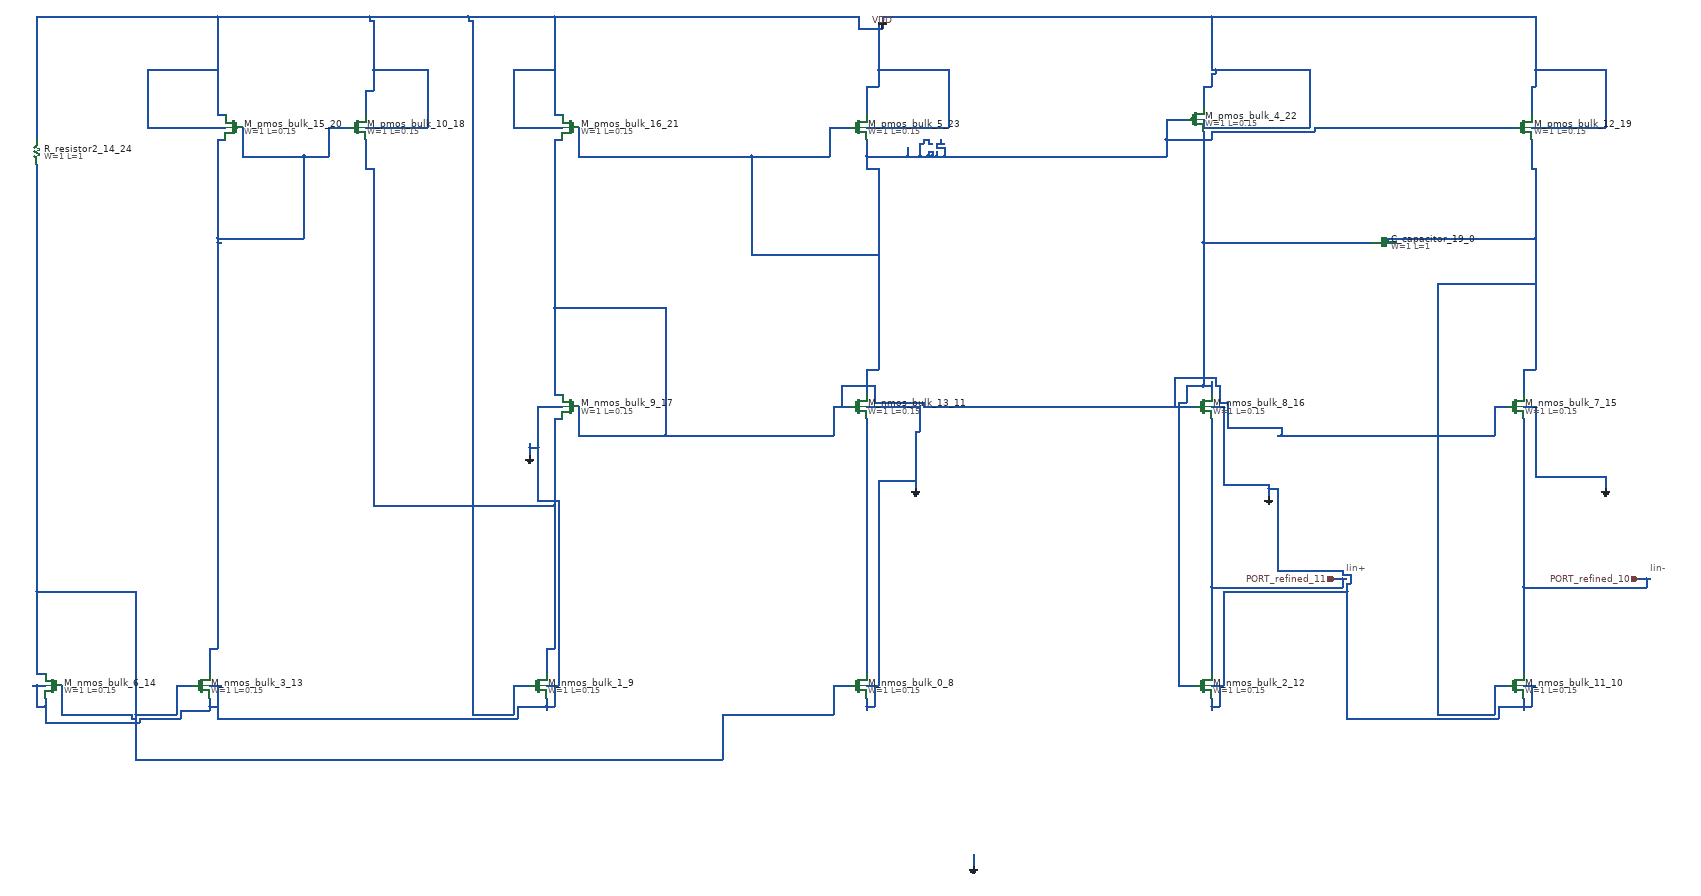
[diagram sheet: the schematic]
v {xschem version=3.4.8 file_version=1.2}
G {}
K {}
V {}
S {}
E {}
C {sky130_fd_pr/cap_mim_m3_1.sym} 3580 700 1 0 {name="C_capacitor_19_0" model=cap_mim_m3_1 W=1 L=1 MF=1 spiceprefix=X}
C {devices/gnd.sym} 1500 1220 0 0 {name="l_gnd_17_1" lab="GND"}
C {devices/gnd.sym} 2440 1300 0 0 {name="l_gnd_18_2" lab="GND"}
C {devices/gnd.sym} 3300 1320 0 0 {name="l_gnd_20_3" lab="GND"}
C {devices/gnd.sym} 4120 1300 0 0 {name="l_gnd_21_4" lab="GND"}
C {devices/gnd.sym} 2580 2220 0 0 {name="l_gnd_22_5" lab="GND"}
C {devices/ipin.sym} 4200 1520 0 0 {name="p_gnd_23_6" lab="PORT_refined_10"}
T {Iin-} 4230 1480 0 0 0.25 0.25 {}
C {devices/ipin.sym} 3460 1520 0 0 {name="p_gnd_24_7" lab="PORT_refined_11"}
T {Iin+} 3490 1480 0 0 0.25 0.25 {}
C {sky130_fd_pr/nfet_01v8.sym} 2300 1780 0 0 {name="M_nmos_bulk_0_8"
W=1
L=0.15
nf=1 
mult=1
ad="expr('int((@nf + 1)/2) * @W / @nf * 0.29')"
pd="expr('2*int((@nf + 1)/2) * (@W / @nf + 0.29)')"
as="expr('int((@nf + 2)/2) * @W / @nf * 0.29')"
ps="expr('2*int((@nf + 2)/2) * (@W / @nf + 0.29)')"
nrd="expr('0.29 / @W ')" nrs="expr('0.29 / @W ')"
sa=0 sb=0 sd=0
model=nfet_01v8
spiceprefix=X
}
C {sky130_fd_pr/nfet_01v8.sym} 1520 1780 0 0 {name="M_nmos_bulk_1_9"
W=1
L=0.15
nf=1 
mult=1
ad="expr('int((@nf + 1)/2) * @W / @nf * 0.29')"
pd="expr('2*int((@nf + 1)/2) * (@W / @nf + 0.29)')"
as="expr('int((@nf + 2)/2) * @W / @nf * 0.29')"
ps="expr('2*int((@nf + 2)/2) * (@W / @nf + 0.29)')"
nrd="expr('0.29 / @W ')" nrs="expr('0.29 / @W ')"
sa=0 sb=0 sd=0
model=nfet_01v8
spiceprefix=X
}
C {sky130_fd_pr/nfet_01v8.sym} 3900 1780 0 0 {name="M_nmos_bulk_11_10"
W=1
L=0.15
nf=1 
mult=1
ad="expr('int((@nf + 1)/2) * @W / @nf * 0.29')"
pd="expr('2*int((@nf + 1)/2) * (@W / @nf + 0.29)')"
as="expr('int((@nf + 2)/2) * @W / @nf * 0.29')"
ps="expr('2*int((@nf + 2)/2) * (@W / @nf + 0.29)')"
nrd="expr('0.29 / @W ')" nrs="expr('0.29 / @W ')"
sa=0 sb=0 sd=0
model=nfet_01v8
spiceprefix=X
}
C {sky130_fd_pr/nfet_01v8.sym} 2300 1100 0 0 {name="M_nmos_bulk_13_11"
W=1
L=0.15
nf=1 
mult=1
ad="expr('int((@nf + 1)/2) * @W / @nf * 0.29')"
pd="expr('2*int((@nf + 1)/2) * (@W / @nf + 0.29)')"
as="expr('int((@nf + 2)/2) * @W / @nf * 0.29')"
ps="expr('2*int((@nf + 2)/2) * (@W / @nf + 0.29)')"
nrd="expr('0.29 / @W ')" nrs="expr('0.29 / @W ')"
sa=0 sb=0 sd=0
model=nfet_01v8
spiceprefix=X
}
C {sky130_fd_pr/nfet_01v8.sym} 3140 1780 0 0 {name="M_nmos_bulk_2_12"
W=1
L=0.15
nf=1 
mult=1
ad="expr('int((@nf + 1)/2) * @W / @nf * 0.29')"
pd="expr('2*int((@nf + 1)/2) * (@W / @nf + 0.29)')"
as="expr('int((@nf + 2)/2) * @W / @nf * 0.29')"
ps="expr('2*int((@nf + 2)/2) * (@W / @nf + 0.29)')"
nrd="expr('0.29 / @W ')" nrs="expr('0.29 / @W ')"
sa=0 sb=0 sd=0
model=nfet_01v8
spiceprefix=X
}
C {sky130_fd_pr/nfet_01v8.sym} 700 1780 0 0 {name="M_nmos_bulk_3_13"
W=1
L=0.15
nf=1 
mult=1
ad="expr('int((@nf + 1)/2) * @W / @nf * 0.29')"
pd="expr('2*int((@nf + 1)/2) * (@W / @nf + 0.29)')"
as="expr('int((@nf + 2)/2) * @W / @nf * 0.29')"
ps="expr('2*int((@nf + 2)/2) * (@W / @nf + 0.29)')"
nrd="expr('0.29 / @W ')" nrs="expr('0.29 / @W ')"
sa=0 sb=0 sd=0
model=nfet_01v8
spiceprefix=X
}
C {sky130_fd_pr/nfet_01v8.sym} 340 1780 0 1 {name="M_nmos_bulk_6_14"
W=1
L=0.15
nf=1 
mult=1
ad="expr('int((@nf + 1)/2) * @W / @nf * 0.29')"
pd="expr('2*int((@nf + 1)/2) * (@W / @nf + 0.29)')"
as="expr('int((@nf + 2)/2) * @W / @nf * 0.29')"
ps="expr('2*int((@nf + 2)/2) * (@W / @nf + 0.29)')"
nrd="expr('0.29 / @W ')" nrs="expr('0.29 / @W ')"
sa=0 sb=0 sd=0
model=nfet_01v8
spiceprefix=X
}
C {sky130_fd_pr/nfet_01v8.sym} 3900 1100 0 0 {name="M_nmos_bulk_7_15"
W=1
L=0.15
nf=1 
mult=1
ad="expr('int((@nf + 1)/2) * @W / @nf * 0.29')"
pd="expr('2*int((@nf + 1)/2) * (@W / @nf + 0.29)')"
as="expr('int((@nf + 2)/2) * @W / @nf * 0.29')"
ps="expr('2*int((@nf + 2)/2) * (@W / @nf + 0.29)')"
nrd="expr('0.29 / @W ')" nrs="expr('0.29 / @W ')"
sa=0 sb=0 sd=0
model=nfet_01v8
spiceprefix=X
}
C {sky130_fd_pr/nfet_01v8.sym} 3140 1100 0 0 {name="M_nmos_bulk_8_16"
W=1
L=0.15
nf=1 
mult=1
ad="expr('int((@nf + 1)/2) * @W / @nf * 0.29')"
pd="expr('2*int((@nf + 1)/2) * (@W / @nf + 0.29)')"
as="expr('int((@nf + 2)/2) * @W / @nf * 0.29')"
ps="expr('2*int((@nf + 2)/2) * (@W / @nf + 0.29)')"
nrd="expr('0.29 / @W ')" nrs="expr('0.29 / @W ')"
sa=0 sb=0 sd=0
model=nfet_01v8
spiceprefix=X
}
C {sky130_fd_pr/nfet_01v8.sym} 1600 1100 0 1 {name="M_nmos_bulk_9_17"
W=1
L=0.15
nf=1 
mult=1
ad="expr('int((@nf + 1)/2) * @W / @nf * 0.29')"
pd="expr('2*int((@nf + 1)/2) * (@W / @nf + 0.29)')"
as="expr('int((@nf + 2)/2) * @W / @nf * 0.29')"
ps="expr('2*int((@nf + 2)/2) * (@W / @nf + 0.29)')"
nrd="expr('0.29 / @W ')" nrs="expr('0.29 / @W ')"
sa=0 sb=0 sd=0
model=nfet_01v8
spiceprefix=X
}
C {sky130_fd_pr/pfet_01v8.sym} 1080 420 0 0 {name="M_pmos_bulk_10_18"
W=1
L=0.15
nf=1
mult=1
ad="expr('int((@nf + 1)/2) * @W / @nf * 0.29')"
pd="expr('2*int((@nf + 1)/2) * (@W / @nf + 0.29)')"
as="expr('int((@nf + 2)/2) * @W / @nf * 0.29')"
ps="expr('2*int((@nf + 2)/2) * (@W / @nf + 0.29)')"
nrd="expr('0.29 / @W ')" nrs="expr('0.29 / @W ')"
sa=0 sb=0 sd=0
model=pfet_01v8
spiceprefix=X
}
C {sky130_fd_pr/pfet_01v8.sym} 3920 420 0 0 {name="M_pmos_bulk_12_19"
W=1
L=0.15
nf=1
mult=1
ad="expr('int((@nf + 1)/2) * @W / @nf * 0.29')"
pd="expr('2*int((@nf + 1)/2) * (@W / @nf + 0.29)')"
as="expr('int((@nf + 2)/2) * @W / @nf * 0.29')"
ps="expr('2*int((@nf + 2)/2) * (@W / @nf + 0.29)')"
nrd="expr('0.29 / @W ')" nrs="expr('0.29 / @W ')"
sa=0 sb=0 sd=0
model=pfet_01v8
spiceprefix=X
}
C {sky130_fd_pr/pfet_01v8.sym} 780 420 0 1 {name="M_pmos_bulk_15_20"
W=1
L=0.15
nf=1
mult=1
ad="expr('int((@nf + 1)/2) * @W / @nf * 0.29')"
pd="expr('2*int((@nf + 1)/2) * (@W / @nf + 0.29)')"
as="expr('int((@nf + 2)/2) * @W / @nf * 0.29')"
ps="expr('2*int((@nf + 2)/2) * (@W / @nf + 0.29)')"
nrd="expr('0.29 / @W ')" nrs="expr('0.29 / @W ')"
sa=0 sb=0 sd=0
model=pfet_01v8
spiceprefix=X
}
C {sky130_fd_pr/pfet_01v8.sym} 1600 420 0 1 {name="M_pmos_bulk_16_21"
W=1
L=0.15
nf=1
mult=1
ad="expr('int((@nf + 1)/2) * @W / @nf * 0.29')"
pd="expr('2*int((@nf + 1)/2) * (@W / @nf + 0.29)')"
as="expr('int((@nf + 2)/2) * @W / @nf * 0.29')"
ps="expr('2*int((@nf + 2)/2) * (@W / @nf + 0.29)')"
nrd="expr('0.29 / @W ')" nrs="expr('0.29 / @W ')"
sa=0 sb=0 sd=0
model=pfet_01v8
spiceprefix=X
}
C {sky130_fd_pr/pfet_01v8.sym} 3120 400 0 0 {name="M_pmos_bulk_4_22"
W=1
L=0.15
nf=1
mult=1
ad="expr('int((@nf + 1)/2) * @W / @nf * 0.29')"
pd="expr('2*int((@nf + 1)/2) * (@W / @nf + 0.29)')"
as="expr('int((@nf + 2)/2) * @W / @nf * 0.29')"
ps="expr('2*int((@nf + 2)/2) * (@W / @nf + 0.29)')"
nrd="expr('0.29 / @W ')" nrs="expr('0.29 / @W ')"
sa=0 sb=0 sd=0
model=pfet_01v8
spiceprefix=X
}
C {sky130_fd_pr/pfet_01v8.sym} 2300 420 0 0 {name="M_pmos_bulk_5_23"
W=1
L=0.15
nf=1
mult=1
ad="expr('int((@nf + 1)/2) * @W / @nf * 0.29')"
pd="expr('2*int((@nf + 1)/2) * (@W / @nf + 0.29)')"
as="expr('int((@nf + 2)/2) * @W / @nf * 0.29')"
ps="expr('2*int((@nf + 2)/2) * (@W / @nf + 0.29)')"
nrd="expr('0.29 / @W ')" nrs="expr('0.29 / @W ')"
sa=0 sb=0 sd=0
model=pfet_01v8
spiceprefix=X
}
C {sky130_fd_pr/res_generic_po.sym} 300 480 2 0 {name="R_resistor2_14_24"
W=1
L=1
model=res_generic_po
spiceprefix=X
mult=1}
C {devices/vdd.sym} 2360 180 0 0 {name="l_vdd_25_25" lab="VDD"}
N 3080 1780 3120 1780 {}
N 3080 1090 3100 1090 {}
N 3100 1050 3140 1050 {}
N 3140 1050 3160 1050 {}
N 3140 700 3550 700 {}
N 3080 1780 3080 1090 {}
N 3100 1090 3100 1050 {}
N 3140 1050 3140 700 {}
N 3140 700 3140 430 {}
N 3160 1070 3160 1050 {}
N 3160 1050 3160 1040 {}
N 3710 1850 3850 1850 {}
N 3850 1780 3880 1780 {}
N 3920 1010 3950 1010 {}
N 3710 800 3950 800 {}
N 3590 700 3610 700 {}
N 3590 690 3950 690 {}
N 3940 520 3950 520 {}
N 3590 700 3590 690 {}
N 3710 1850 3710 800 {}
N 3850 1850 3850 1780 {}
N 3920 1070 3920 1010 {}
N 3940 520 3940 450 {}
N 3950 1010 3950 800 {}
N 3950 800 3950 690 {}
N 3950 690 3950 520 {}
N 3920 1540 4220 1540 {}
N 4200 1520 4220 1520 {}
N 4220 1520 4230 1520 {}
N 3920 1750 3920 1540 {}
N 3920 1540 3920 1130 {}
N 4220 1540 4220 1520 {}
N 3160 1540 3480 1540 {}
N 3460 1520 3480 1520 {}
N 3480 1520 3490 1520 {}
N 3160 1750 3160 1540 {}
N 3160 1540 3160 1130 {}
N 3480 1540 3480 1520 {}
N 2320 1750 2320 1130 {}
N 320 1870 550 1870 {}
N 550 1860 650 1860 {}
N 740 1860 1470 1860 {}
N 3490 1860 3860 1860 {}
N 650 1840 720 1840 {}
N 300 1830 320 1830 {}
N 720 1830 740 1830 {}
N 1470 1830 1540 1830 {}
N 1540 1830 1560 1830 {}
N 2320 1830 2340 1830 {}
N 3160 1830 3180 1830 {}
N 3860 1830 3920 1830 {}
N 3920 1830 3940 1830 {}
N 290 1780 300 1780 {}
N 300 1780 320 1780 {}
N 720 1780 740 1780 {}
N 740 1780 750 1780 {}
N 1540 1780 1560 1780 {}
N 1560 1780 1570 1780 {}
N 2320 1780 2340 1780 {}
N 2340 1780 2350 1780 {}
N 3160 1780 3180 1780 {}
N 3180 1780 3190 1780 {}
N 3920 1780 3940 1780 {}
N 3940 1780 3950 1780 {}
N 3190 1550 3490 1550 {}
N 3490 1530 3500 1530 {}
N 3480 1510 3500 1510 {}
N 3320 1500 3480 1500 {}
N 1520 1330 1570 1330 {}
N 3300 1300 3320 1300 {}
N 3190 1290 3300 1290 {}
N 2350 1280 2440 1280 {}
N 3950 1270 4120 1270 {}
N 1500 1200 1520 1200 {}
N 2440 1160 2450 1160 {}
N 1520 1100 1580 1100 {}
N 2320 1100 2450 1100 {}
N 3160 1100 3190 1100 {}
N 3920 1100 3950 1100 {}
N 300 1830 300 1780 {}
N 320 1870 320 1830 {}
N 320 1830 320 1810 {}
N 550 1870 550 1860 {}
N 650 1860 650 1840 {}
N 720 1840 720 1830 {}
N 720 1830 720 1810 {}
N 740 1860 740 1830 {}
N 740 1830 740 1780 {}
N 1470 1860 1470 1830 {}
N 1500 1220 1500 1200 {}
N 1500 1200 1500 1190 {}
N 1520 1330 1520 1200 {}
N 1520 1200 1520 1100 {}
N 1540 1840 1540 1830 {}
N 1540 1830 1540 1810 {}
N 1560 1830 1560 1780 {}
N 1570 1780 1570 1330 {}
N 2320 1840 2320 1830 {}
N 2320 1830 2320 1810 {}
N 2340 1830 2340 1780 {}
N 2350 1780 2350 1280 {}
N 2440 1300 2440 1280 {}
N 2440 1280 2440 1160 {}
N 2450 1160 2450 1100 {}
N 2580 2220 2580 2190 {}
N 3160 1840 3160 1830 {}
N 3160 1830 3160 1810 {}
N 3180 1830 3180 1780 {}
N 3190 1780 3190 1550 {}
N 3190 1290 3190 1100 {}
N 3300 1320 3300 1300 {}
N 3300 1300 3300 1290 {}
N 3320 1500 3320 1300 {}
N 3480 1510 3480 1500 {}
N 3490 1860 3490 1550 {}
N 3490 1550 3490 1530 {}
N 3500 1530 3500 1510 {}
N 3860 1860 3860 1830 {}
N 3920 1840 3920 1830 {}
N 3920 1830 3920 1810 {}
N 3940 1830 3940 1780 {}
N 3950 1270 3950 1100 {}
N 4120 1300 4120 1270 {}
N 540 1960 1970 1960 {}
N 530 1860 540 1860 {}
N 360 1850 530 1850 {}
N 540 1850 640 1850 {}
N 1970 1850 2240 1850 {}
N 640 1780 680 1780 {}
N 2240 1780 2280 1780 {}
N 300 1750 320 1750 {}
N 300 1550 540 1550 {}
N 300 1750 300 1550 {}
N 300 1550 300 510 {}
N 360 1850 360 1780 {}
N 530 1860 530 1850 {}
N 540 1960 540 1860 {}
N 540 1860 540 1850 {}
N 540 1850 540 1550 {}
N 640 1850 640 1780 {}
N 1970 1960 1970 1850 {}
N 2240 1850 2240 1780 {}
N 1540 1690 1560 1690 {}
N 1120 1340 1560 1340 {}
N 1560 1130 1580 1130 {}
N 1100 520 1120 520 {}
N 1100 520 1100 450 {}
N 1120 1340 1120 520 {}
N 1540 1750 1540 1690 {}
N 1560 1690 1560 1340 {}
N 1560 1340 1560 1130 {}
N 1360 1850 1460 1850 {}
N 1460 1780 1500 1780 {}
N 570 420 760 420 {}
N 1100 420 1250 420 {}
N 1460 420 1580 420 {}
N 2320 420 2520 420 {}
N 3140 420 3400 420 {}
N 3940 420 4120 420 {}
N 740 390 760 390 {}
N 1560 390 1580 390 {}
N 1100 330 1120 330 {}
N 2320 320 2350 320 {}
N 3140 320 3160 320 {}
N 3940 320 3950 320 {}
N 3160 290 3170 290 {}
N 570 280 740 280 {}
N 1120 280 1250 280 {}
N 1460 280 1560 280 {}
N 2350 280 2520 280 {}
N 3160 280 3170 280 {}
N 3170 280 3400 280 {}
N 3950 280 4120 280 {}
N 2300 180 2350 180 {}
N 2350 180 2360 180 {}
N 1110 160 1120 160 {}
N 1350 160 1360 160 {}
N 300 150 740 150 {}
N 740 150 1110 150 {}
N 1110 150 1350 150 {}
N 1350 150 1560 150 {}
N 1560 150 2300 150 {}
N 2360 150 3160 150 {}
N 3160 150 3950 150 {}
N 300 450 300 150 {}
N 570 420 570 280 {}
N 740 390 740 280 {}
N 740 280 740 150 {}
N 1100 390 1100 330 {}
N 1110 160 1110 150 {}
N 1120 330 1120 280 {}
N 1120 280 1120 160 {}
N 1250 420 1250 280 {}
N 1350 160 1350 150 {}
N 1360 1850 1360 160 {}
N 1460 1850 1460 1780 {}
N 1460 420 1460 280 {}
N 1560 390 1560 280 {}
N 1560 280 1560 150 {}
N 2300 180 2300 150 {}
N 2320 390 2320 320 {}
N 2350 320 2350 280 {}
N 2350 280 2350 180 {}
N 2350 180 2350 170 {}
N 2360 180 2360 150 {}
N 2520 420 2520 280 {}
N 3140 420 3140 400 {}
N 3140 370 3140 320 {}
N 3160 320 3160 290 {}
N 3160 280 3160 150 {}
N 3170 290 3170 280 {}
N 3400 420 3400 280 {}
N 3940 390 3940 320 {}
N 3950 320 3950 280 {}
N 3950 280 3950 150 {}
N 4120 420 4120 280 {}
N 2320 1010 2350 1010 {}
N 2040 730 2350 730 {}
N 2320 520 2350 520 {}
N 1620 490 2040 490 {}
N 2040 490 2230 490 {}
N 2320 490 2420 490 {}
N 2420 490 2450 490 {}
N 2450 490 2470 490 {}
N 2470 490 2480 490 {}
N 2480 490 2490 490 {}
N 2490 490 2510 490 {}
N 2510 490 3050 490 {}
N 2470 480 2480 480 {}
N 2490 470 2510 470 {}
N 2450 460 2460 460 {}
N 2470 460 2480 460 {}
N 2490 460 2500 460 {}
N 2500 460 2510 460 {}
N 2460 450 2470 450 {}
N 3050 450 3160 450 {}
N 3160 430 3410 430 {}
N 2230 420 2280 420 {}
N 3410 420 3900 420 {}
N 3050 400 3100 400 {}
N 1620 490 1620 420 {}
N 2040 730 2040 490 {}
N 2230 490 2230 420 {}
N 2320 1070 2320 1010 {}
N 2320 520 2320 490 {}
N 2320 490 2320 450 {}
N 2350 1010 2350 730 {}
N 2350 730 2350 520 {}
N 2420 490 2420 470 {}
N 2450 490 2450 460 {}
N 2460 460 2460 450 {}
N 2470 490 2470 480 {}
N 2470 460 2470 450 {}
N 2480 490 2480 480 {}
N 2490 490 2490 480 {}
N 2490 470 2490 460 {}
N 2500 460 2500 450 {}
N 2510 490 2510 470 {}
N 3050 490 3050 450 {}
N 3050 450 3050 400 {}
N 3160 450 3160 430 {}
N 3410 430 3410 420 {}
N 1620 1170 1830 1170 {}
N 1830 1170 2240 1170 {}
N 3320 1170 3330 1170 {}
N 3330 1170 3850 1170 {}
N 3200 1150 3330 1150 {}
N 2240 1100 2260 1100 {}
N 2260 1100 2280 1100 {}
N 2460 1100 3070 1100 {}
N 3070 1100 3120 1100 {}
N 3850 1100 3880 1100 {}
N 2340 1090 2460 1090 {}
N 3180 1090 3200 1090 {}
N 1560 1070 1580 1070 {}
N 2260 1050 2340 1050 {}
N 3170 1050 3180 1050 {}
N 3070 1030 3170 1030 {}
N 1560 860 1830 860 {}
N 1560 450 1580 450 {}
N 1560 1070 1560 860 {}
N 1560 860 1560 450 {}
N 1620 1170 1620 1100 {}
N 1830 1170 1830 860 {}
N 2240 1170 2240 1100 {}
N 2260 1100 2260 1050 {}
N 2340 1090 2340 1050 {}
N 2460 1100 2460 1090 {}
N 3070 1100 3070 1030 {}
N 3170 1050 3170 1030 {}
N 3180 1090 3180 1050 {}
N 3200 1150 3200 1090 {}
N 3330 1170 3330 1150 {}
N 3850 1170 3850 1100 {}
N 720 1690 740 1690 {}
N 740 700 750 700 {}
N 740 690 950 690 {}
N 800 490 950 490 {}
N 950 490 1010 490 {}
N 740 450 760 450 {}
N 1010 420 1060 420 {}
N 720 1750 720 1690 {}
N 740 1690 740 700 {}
N 740 700 740 690 {}
N 740 690 740 450 {}
N 800 490 800 420 {}
N 950 690 950 490 {}
N 1010 490 1010 420 {}
